# Generated deterministically by seda-macro-lef-normalizer-v1; recipe orfs-ng45-fakeram-metal3-coupledl2-pg-v1.
VERSION 5.8 ;
BUSBITCHARS "[]" ;
DIVIDERCHAR "/" ;

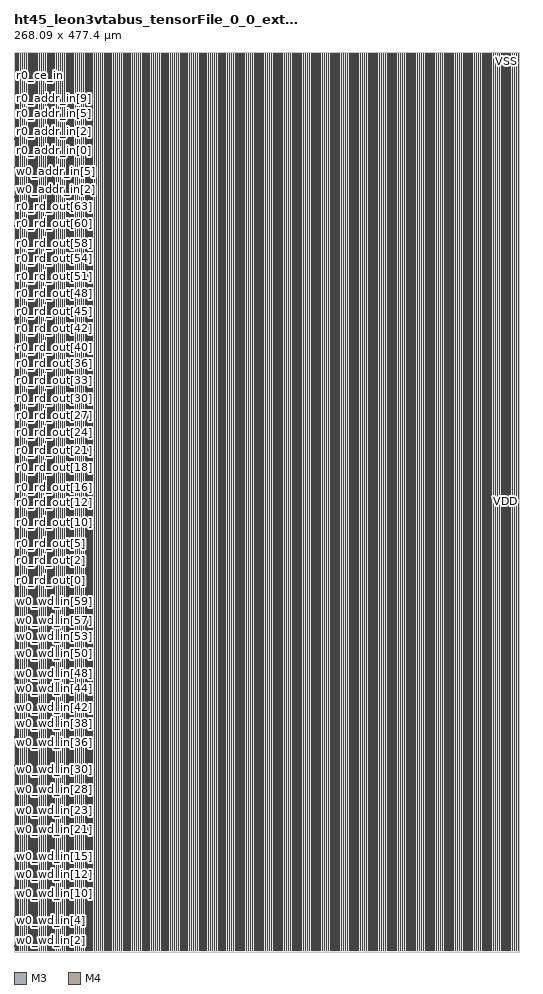
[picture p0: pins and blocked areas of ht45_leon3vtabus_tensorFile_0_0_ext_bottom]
MACRO ht45_leon3vtabus_tensorFile_0_0_ext_bottom
  FOREIGN ht45_leon3vtabus_tensorFile_0_0_ext_bottom 0 0 ;
  CLASS BLOCK ;
  ORIGIN 0 0 ;
  SIZE 268.09 BY 477.4 ;
  SYMMETRY X Y R90 ;
  PIN w0_wd_in[0]
    DIRECTION INPUT ;
    USE SIGNAL ;
    SHAPE ABUTMENT ;
    PORT
      LAYER M3 ;
      RECT 0 0.035 0.07 0.105 ;
    END
  END w0_wd_in[0]
  PIN w0_wd_in[1]
    DIRECTION INPUT ;
    USE SIGNAL ;
    SHAPE ABUTMENT ;
    PORT
      LAYER M3 ;
      RECT 0 3.115 0.07 3.185 ;
    END
  END w0_wd_in[1]
  PIN w0_wd_in[2]
    DIRECTION INPUT ;
    USE SIGNAL ;
    SHAPE ABUTMENT ;
    PORT
      LAYER M3 ;
      RECT 0 6.195 0.07 6.265 ;
    END
  END w0_wd_in[2]
  PIN w0_wd_in[3]
    DIRECTION INPUT ;
    USE SIGNAL ;
    SHAPE ABUTMENT ;
    PORT
      LAYER M3 ;
      RECT 0 9.275 0.07 9.345 ;
    END
  END w0_wd_in[3]
  PIN w0_wd_in[4]
    DIRECTION INPUT ;
    USE SIGNAL ;
    SHAPE ABUTMENT ;
    PORT
      LAYER M3 ;
      RECT 0 12.355 0.07 12.425 ;
    END
  END w0_wd_in[4]
  PIN w0_wd_in[5]
    DIRECTION INPUT ;
    USE SIGNAL ;
    SHAPE ABUTMENT ;
    PORT
      LAYER M3 ;
      RECT 0 15.435 0.07 15.505 ;
    END
  END w0_wd_in[5]
  PIN w0_wd_in[6]
    DIRECTION INPUT ;
    USE SIGNAL ;
    SHAPE ABUTMENT ;
    PORT
      LAYER M3 ;
      RECT 0 18.515 0.07 18.585 ;
    END
  END w0_wd_in[6]
  PIN w0_wd_in[7]
    DIRECTION INPUT ;
    USE SIGNAL ;
    SHAPE ABUTMENT ;
    PORT
      LAYER M3 ;
      RECT 0 21.595 0.07 21.665 ;
    END
  END w0_wd_in[7]
  PIN w0_wd_in[8]
    DIRECTION INPUT ;
    USE SIGNAL ;
    SHAPE ABUTMENT ;
    PORT
      LAYER M3 ;
      RECT 0 24.675 0.07 24.745 ;
    END
  END w0_wd_in[8]
  PIN w0_wd_in[9]
    DIRECTION INPUT ;
    USE SIGNAL ;
    SHAPE ABUTMENT ;
    PORT
      LAYER M3 ;
      RECT 0 27.755 0.07 27.825 ;
    END
  END w0_wd_in[9]
  PIN w0_wd_in[10]
    DIRECTION INPUT ;
    USE SIGNAL ;
    SHAPE ABUTMENT ;
    PORT
      LAYER M3 ;
      RECT 0 30.835 0.07 30.905 ;
    END
  END w0_wd_in[10]
  PIN w0_wd_in[11]
    DIRECTION INPUT ;
    USE SIGNAL ;
    SHAPE ABUTMENT ;
    PORT
      LAYER M3 ;
      RECT 0 33.915 0.07 33.985 ;
    END
  END w0_wd_in[11]
  PIN w0_wd_in[12]
    DIRECTION INPUT ;
    USE SIGNAL ;
    SHAPE ABUTMENT ;
    PORT
      LAYER M3 ;
      RECT 0 36.995 0.07 37.065 ;
    END
  END w0_wd_in[12]
  PIN w0_wd_in[13]
    DIRECTION INPUT ;
    USE SIGNAL ;
    SHAPE ABUTMENT ;
    PORT
      LAYER M3 ;
      RECT 0 40.075 0.07 40.145 ;
    END
  END w0_wd_in[13]
  PIN w0_wd_in[14]
    DIRECTION INPUT ;
    USE SIGNAL ;
    SHAPE ABUTMENT ;
    PORT
      LAYER M3 ;
      RECT 0 43.155 0.07 43.225 ;
    END
  END w0_wd_in[14]
  PIN w0_wd_in[15]
    DIRECTION INPUT ;
    USE SIGNAL ;
    SHAPE ABUTMENT ;
    PORT
      LAYER M3 ;
      RECT 0 46.235 0.07 46.305 ;
    END
  END w0_wd_in[15]
  PIN w0_wd_in[16]
    DIRECTION INPUT ;
    USE SIGNAL ;
    SHAPE ABUTMENT ;
    PORT
      LAYER M3 ;
      RECT 0 49.315 0.07 49.385 ;
    END
  END w0_wd_in[16]
  PIN w0_wd_in[17]
    DIRECTION INPUT ;
    USE SIGNAL ;
    SHAPE ABUTMENT ;
    PORT
      LAYER M3 ;
      RECT 0 52.395 0.07 52.465 ;
    END
  END w0_wd_in[17]
  PIN w0_wd_in[18]
    DIRECTION INPUT ;
    USE SIGNAL ;
    SHAPE ABUTMENT ;
    PORT
      LAYER M3 ;
      RECT 0 55.475 0.07 55.545 ;
    END
  END w0_wd_in[18]
  PIN w0_wd_in[19]
    DIRECTION INPUT ;
    USE SIGNAL ;
    SHAPE ABUTMENT ;
    PORT
      LAYER M3 ;
      RECT 0 58.555 0.07 58.625 ;
    END
  END w0_wd_in[19]
  PIN w0_wd_in[20]
    DIRECTION INPUT ;
    USE SIGNAL ;
    SHAPE ABUTMENT ;
    PORT
      LAYER M3 ;
      RECT 0 61.635 0.07 61.705 ;
    END
  END w0_wd_in[20]
  PIN w0_wd_in[21]
    DIRECTION INPUT ;
    USE SIGNAL ;
    SHAPE ABUTMENT ;
    PORT
      LAYER M3 ;
      RECT 0 64.715 0.07 64.785 ;
    END
  END w0_wd_in[21]
  PIN w0_wd_in[22]
    DIRECTION INPUT ;
    USE SIGNAL ;
    SHAPE ABUTMENT ;
    PORT
      LAYER M3 ;
      RECT 0 67.795 0.07 67.865 ;
    END
  END w0_wd_in[22]
  PIN w0_wd_in[23]
    DIRECTION INPUT ;
    USE SIGNAL ;
    SHAPE ABUTMENT ;
    PORT
      LAYER M3 ;
      RECT 0 70.875 0.07 70.945 ;
    END
  END w0_wd_in[23]
  PIN w0_wd_in[24]
    DIRECTION INPUT ;
    USE SIGNAL ;
    SHAPE ABUTMENT ;
    PORT
      LAYER M3 ;
      RECT 0 73.955 0.07 74.025 ;
    END
  END w0_wd_in[24]
  PIN w0_wd_in[25]
    DIRECTION INPUT ;
    USE SIGNAL ;
    SHAPE ABUTMENT ;
    PORT
      LAYER M3 ;
      RECT 0 77.035 0.07 77.105 ;
    END
  END w0_wd_in[25]
  PIN w0_wd_in[26]
    DIRECTION INPUT ;
    USE SIGNAL ;
    SHAPE ABUTMENT ;
    PORT
      LAYER M3 ;
      RECT 0 80.115 0.07 80.185 ;
    END
  END w0_wd_in[26]
  PIN w0_wd_in[27]
    DIRECTION INPUT ;
    USE SIGNAL ;
    SHAPE ABUTMENT ;
    PORT
      LAYER M3 ;
      RECT 0 83.195 0.07 83.265 ;
    END
  END w0_wd_in[27]
  PIN w0_wd_in[28]
    DIRECTION INPUT ;
    USE SIGNAL ;
    SHAPE ABUTMENT ;
    PORT
      LAYER M3 ;
      RECT 0 86.275 0.07 86.345 ;
    END
  END w0_wd_in[28]
  PIN w0_wd_in[29]
    DIRECTION INPUT ;
    USE SIGNAL ;
    SHAPE ABUTMENT ;
    PORT
      LAYER M3 ;
      RECT 0 89.355 0.07 89.425 ;
    END
  END w0_wd_in[29]
  PIN w0_wd_in[30]
    DIRECTION INPUT ;
    USE SIGNAL ;
    SHAPE ABUTMENT ;
    PORT
      LAYER M3 ;
      RECT 0 92.435 0.07 92.505 ;
    END
  END w0_wd_in[30]
  PIN w0_wd_in[31]
    DIRECTION INPUT ;
    USE SIGNAL ;
    SHAPE ABUTMENT ;
    PORT
      LAYER M3 ;
      RECT 0 95.515 0.07 95.585 ;
    END
  END w0_wd_in[31]
  PIN w0_wd_in[32]
    DIRECTION INPUT ;
    USE SIGNAL ;
    SHAPE ABUTMENT ;
    PORT
      LAYER M3 ;
      RECT 0 98.595 0.07 98.665 ;
    END
  END w0_wd_in[32]
  PIN w0_wd_in[33]
    DIRECTION INPUT ;
    USE SIGNAL ;
    SHAPE ABUTMENT ;
    PORT
      LAYER M3 ;
      RECT 0 101.675 0.07 101.745 ;
    END
  END w0_wd_in[33]
  PIN w0_wd_in[34]
    DIRECTION INPUT ;
    USE SIGNAL ;
    SHAPE ABUTMENT ;
    PORT
      LAYER M3 ;
      RECT 0 104.755 0.07 104.825 ;
    END
  END w0_wd_in[34]
  PIN w0_wd_in[35]
    DIRECTION INPUT ;
    USE SIGNAL ;
    SHAPE ABUTMENT ;
    PORT
      LAYER M3 ;
      RECT 0 107.835 0.07 107.905 ;
    END
  END w0_wd_in[35]
  PIN w0_wd_in[36]
    DIRECTION INPUT ;
    USE SIGNAL ;
    SHAPE ABUTMENT ;
    PORT
      LAYER M3 ;
      RECT 0 110.915 0.07 110.985 ;
    END
  END w0_wd_in[36]
  PIN w0_wd_in[37]
    DIRECTION INPUT ;
    USE SIGNAL ;
    SHAPE ABUTMENT ;
    PORT
      LAYER M3 ;
      RECT 0 113.995 0.07 114.065 ;
    END
  END w0_wd_in[37]
  PIN w0_wd_in[38]
    DIRECTION INPUT ;
    USE SIGNAL ;
    SHAPE ABUTMENT ;
    PORT
      LAYER M3 ;
      RECT 0 117.075 0.07 117.145 ;
    END
  END w0_wd_in[38]
  PIN w0_wd_in[39]
    DIRECTION INPUT ;
    USE SIGNAL ;
    SHAPE ABUTMENT ;
    PORT
      LAYER M3 ;
      RECT 0 120.155 0.07 120.225 ;
    END
  END w0_wd_in[39]
  PIN w0_wd_in[40]
    DIRECTION INPUT ;
    USE SIGNAL ;
    SHAPE ABUTMENT ;
    PORT
      LAYER M3 ;
      RECT 0 123.235 0.07 123.305 ;
    END
  END w0_wd_in[40]
  PIN w0_wd_in[41]
    DIRECTION INPUT ;
    USE SIGNAL ;
    SHAPE ABUTMENT ;
    PORT
      LAYER M3 ;
      RECT 0 126.315 0.07 126.385 ;
    END
  END w0_wd_in[41]
  PIN w0_wd_in[42]
    DIRECTION INPUT ;
    USE SIGNAL ;
    SHAPE ABUTMENT ;
    PORT
      LAYER M3 ;
      RECT 0 129.395 0.07 129.465 ;
    END
  END w0_wd_in[42]
  PIN w0_wd_in[43]
    DIRECTION INPUT ;
    USE SIGNAL ;
    SHAPE ABUTMENT ;
    PORT
      LAYER M3 ;
      RECT 0 132.475 0.07 132.545 ;
    END
  END w0_wd_in[43]
  PIN w0_wd_in[44]
    DIRECTION INPUT ;
    USE SIGNAL ;
    SHAPE ABUTMENT ;
    PORT
      LAYER M3 ;
      RECT 0 135.555 0.07 135.625 ;
    END
  END w0_wd_in[44]
  PIN w0_wd_in[45]
    DIRECTION INPUT ;
    USE SIGNAL ;
    SHAPE ABUTMENT ;
    PORT
      LAYER M3 ;
      RECT 0 138.635 0.07 138.705 ;
    END
  END w0_wd_in[45]
  PIN w0_wd_in[46]
    DIRECTION INPUT ;
    USE SIGNAL ;
    SHAPE ABUTMENT ;
    PORT
      LAYER M3 ;
      RECT 0 141.715 0.07 141.785 ;
    END
  END w0_wd_in[46]
  PIN w0_wd_in[47]
    DIRECTION INPUT ;
    USE SIGNAL ;
    SHAPE ABUTMENT ;
    PORT
      LAYER M3 ;
      RECT 0 144.795 0.07 144.865 ;
    END
  END w0_wd_in[47]
  PIN w0_wd_in[48]
    DIRECTION INPUT ;
    USE SIGNAL ;
    SHAPE ABUTMENT ;
    PORT
      LAYER M3 ;
      RECT 0 147.875 0.07 147.945 ;
    END
  END w0_wd_in[48]
  PIN w0_wd_in[49]
    DIRECTION INPUT ;
    USE SIGNAL ;
    SHAPE ABUTMENT ;
    PORT
      LAYER M3 ;
      RECT 0 150.955 0.07 151.025 ;
    END
  END w0_wd_in[49]
  PIN w0_wd_in[50]
    DIRECTION INPUT ;
    USE SIGNAL ;
    SHAPE ABUTMENT ;
    PORT
      LAYER M3 ;
      RECT 0 154.035 0.07 154.105 ;
    END
  END w0_wd_in[50]
  PIN w0_wd_in[51]
    DIRECTION INPUT ;
    USE SIGNAL ;
    SHAPE ABUTMENT ;
    PORT
      LAYER M3 ;
      RECT 0 157.115 0.07 157.185 ;
    END
  END w0_wd_in[51]
  PIN w0_wd_in[52]
    DIRECTION INPUT ;
    USE SIGNAL ;
    SHAPE ABUTMENT ;
    PORT
      LAYER M3 ;
      RECT 0 160.195 0.07 160.265 ;
    END
  END w0_wd_in[52]
  PIN w0_wd_in[53]
    DIRECTION INPUT ;
    USE SIGNAL ;
    SHAPE ABUTMENT ;
    PORT
      LAYER M3 ;
      RECT 0 163.275 0.07 163.345 ;
    END
  END w0_wd_in[53]
  PIN w0_wd_in[54]
    DIRECTION INPUT ;
    USE SIGNAL ;
    SHAPE ABUTMENT ;
    PORT
      LAYER M3 ;
      RECT 0 166.355 0.07 166.425 ;
    END
  END w0_wd_in[54]
  PIN w0_wd_in[55]
    DIRECTION INPUT ;
    USE SIGNAL ;
    SHAPE ABUTMENT ;
    PORT
      LAYER M3 ;
      RECT 0 169.435 0.07 169.505 ;
    END
  END w0_wd_in[55]
  PIN w0_wd_in[56]
    DIRECTION INPUT ;
    USE SIGNAL ;
    SHAPE ABUTMENT ;
    PORT
      LAYER M3 ;
      RECT 0 172.515 0.07 172.585 ;
    END
  END w0_wd_in[56]
  PIN w0_wd_in[57]
    DIRECTION INPUT ;
    USE SIGNAL ;
    SHAPE ABUTMENT ;
    PORT
      LAYER M3 ;
      RECT 0 175.595 0.07 175.665 ;
    END
  END w0_wd_in[57]
  PIN w0_wd_in[58]
    DIRECTION INPUT ;
    USE SIGNAL ;
    SHAPE ABUTMENT ;
    PORT
      LAYER M3 ;
      RECT 0 178.675 0.07 178.745 ;
    END
  END w0_wd_in[58]
  PIN w0_wd_in[59]
    DIRECTION INPUT ;
    USE SIGNAL ;
    SHAPE ABUTMENT ;
    PORT
      LAYER M3 ;
      RECT 0 181.755 0.07 181.825 ;
    END
  END w0_wd_in[59]
  PIN w0_wd_in[60]
    DIRECTION INPUT ;
    USE SIGNAL ;
    SHAPE ABUTMENT ;
    PORT
      LAYER M3 ;
      RECT 0 184.835 0.07 184.905 ;
    END
  END w0_wd_in[60]
  PIN w0_wd_in[61]
    DIRECTION INPUT ;
    USE SIGNAL ;
    SHAPE ABUTMENT ;
    PORT
      LAYER M3 ;
      RECT 0 187.915 0.07 187.985 ;
    END
  END w0_wd_in[61]
  PIN w0_wd_in[62]
    DIRECTION INPUT ;
    USE SIGNAL ;
    SHAPE ABUTMENT ;
    PORT
      LAYER M3 ;
      RECT 0 190.995 0.07 191.065 ;
    END
  END w0_wd_in[62]
  PIN w0_wd_in[63]
    DIRECTION INPUT ;
    USE SIGNAL ;
    SHAPE ABUTMENT ;
    PORT
      LAYER M3 ;
      RECT 0 194.075 0.07 194.145 ;
    END
  END w0_wd_in[63]
  PIN r0_rd_out[0]
    DIRECTION OUTPUT ;
    USE SIGNAL ;
    SHAPE ABUTMENT ;
    PORT
      LAYER M3 ;
      RECT 0 197.155 0.07 197.225 ;
    END
  END r0_rd_out[0]
  PIN r0_rd_out[1]
    DIRECTION OUTPUT ;
    USE SIGNAL ;
    SHAPE ABUTMENT ;
    PORT
      LAYER M3 ;
      RECT 0 200.235 0.07 200.305 ;
    END
  END r0_rd_out[1]
  PIN r0_rd_out[2]
    DIRECTION OUTPUT ;
    USE SIGNAL ;
    SHAPE ABUTMENT ;
    PORT
      LAYER M3 ;
      RECT 0 203.315 0.07 203.385 ;
    END
  END r0_rd_out[2]
  PIN r0_rd_out[3]
    DIRECTION OUTPUT ;
    USE SIGNAL ;
    SHAPE ABUTMENT ;
    PORT
      LAYER M3 ;
      RECT 0 206.395 0.07 206.465 ;
    END
  END r0_rd_out[3]
  PIN r0_rd_out[4]
    DIRECTION OUTPUT ;
    USE SIGNAL ;
    SHAPE ABUTMENT ;
    PORT
      LAYER M3 ;
      RECT 0 209.475 0.07 209.545 ;
    END
  END r0_rd_out[4]
  PIN r0_rd_out[5]
    DIRECTION OUTPUT ;
    USE SIGNAL ;
    SHAPE ABUTMENT ;
    PORT
      LAYER M3 ;
      RECT 0 212.555 0.07 212.625 ;
    END
  END r0_rd_out[5]
  PIN r0_rd_out[6]
    DIRECTION OUTPUT ;
    USE SIGNAL ;
    SHAPE ABUTMENT ;
    PORT
      LAYER M3 ;
      RECT 0 215.635 0.07 215.705 ;
    END
  END r0_rd_out[6]
  PIN r0_rd_out[7]
    DIRECTION OUTPUT ;
    USE SIGNAL ;
    SHAPE ABUTMENT ;
    PORT
      LAYER M3 ;
      RECT 0 218.715 0.07 218.785 ;
    END
  END r0_rd_out[7]
  PIN r0_rd_out[8]
    DIRECTION OUTPUT ;
    USE SIGNAL ;
    SHAPE ABUTMENT ;
    PORT
      LAYER M3 ;
      RECT 0 221.795 0.07 221.865 ;
    END
  END r0_rd_out[8]
  PIN r0_rd_out[9]
    DIRECTION OUTPUT ;
    USE SIGNAL ;
    SHAPE ABUTMENT ;
    PORT
      LAYER M3 ;
      RECT 0 224.875 0.07 224.945 ;
    END
  END r0_rd_out[9]
  PIN r0_rd_out[10]
    DIRECTION OUTPUT ;
    USE SIGNAL ;
    SHAPE ABUTMENT ;
    PORT
      LAYER M3 ;
      RECT 0 227.955 0.07 228.025 ;
    END
  END r0_rd_out[10]
  PIN r0_rd_out[11]
    DIRECTION OUTPUT ;
    USE SIGNAL ;
    SHAPE ABUTMENT ;
    PORT
      LAYER M3 ;
      RECT 0 231.035 0.07 231.105 ;
    END
  END r0_rd_out[11]
  PIN r0_rd_out[12]
    DIRECTION OUTPUT ;
    USE SIGNAL ;
    SHAPE ABUTMENT ;
    PORT
      LAYER M3 ;
      RECT 0 234.115 0.07 234.185 ;
    END
  END r0_rd_out[12]
  PIN r0_rd_out[13]
    DIRECTION OUTPUT ;
    USE SIGNAL ;
    SHAPE ABUTMENT ;
    PORT
      LAYER M3 ;
      RECT 0 237.195 0.07 237.265 ;
    END
  END r0_rd_out[13]
  PIN r0_rd_out[14]
    DIRECTION OUTPUT ;
    USE SIGNAL ;
    SHAPE ABUTMENT ;
    PORT
      LAYER M3 ;
      RECT 0 240.275 0.07 240.345 ;
    END
  END r0_rd_out[14]
  PIN r0_rd_out[15]
    DIRECTION OUTPUT ;
    USE SIGNAL ;
    SHAPE ABUTMENT ;
    PORT
      LAYER M3 ;
      RECT 0 243.355 0.07 243.425 ;
    END
  END r0_rd_out[15]
  PIN r0_rd_out[16]
    DIRECTION OUTPUT ;
    USE SIGNAL ;
    SHAPE ABUTMENT ;
    PORT
      LAYER M3 ;
      RECT 0 246.435 0.07 246.505 ;
    END
  END r0_rd_out[16]
  PIN r0_rd_out[17]
    DIRECTION OUTPUT ;
    USE SIGNAL ;
    SHAPE ABUTMENT ;
    PORT
      LAYER M3 ;
      RECT 0 249.515 0.07 249.585 ;
    END
  END r0_rd_out[17]
  PIN r0_rd_out[18]
    DIRECTION OUTPUT ;
    USE SIGNAL ;
    SHAPE ABUTMENT ;
    PORT
      LAYER M3 ;
      RECT 0 252.595 0.07 252.665 ;
    END
  END r0_rd_out[18]
  PIN r0_rd_out[19]
    DIRECTION OUTPUT ;
    USE SIGNAL ;
    SHAPE ABUTMENT ;
    PORT
      LAYER M3 ;
      RECT 0 255.675 0.07 255.745 ;
    END
  END r0_rd_out[19]
  PIN r0_rd_out[20]
    DIRECTION OUTPUT ;
    USE SIGNAL ;
    SHAPE ABUTMENT ;
    PORT
      LAYER M3 ;
      RECT 0 258.755 0.07 258.825 ;
    END
  END r0_rd_out[20]
  PIN r0_rd_out[21]
    DIRECTION OUTPUT ;
    USE SIGNAL ;
    SHAPE ABUTMENT ;
    PORT
      LAYER M3 ;
      RECT 0 261.835 0.07 261.905 ;
    END
  END r0_rd_out[21]
  PIN r0_rd_out[22]
    DIRECTION OUTPUT ;
    USE SIGNAL ;
    SHAPE ABUTMENT ;
    PORT
      LAYER M3 ;
      RECT 0 264.915 0.07 264.985 ;
    END
  END r0_rd_out[22]
  PIN r0_rd_out[23]
    DIRECTION OUTPUT ;
    USE SIGNAL ;
    SHAPE ABUTMENT ;
    PORT
      LAYER M3 ;
      RECT 0 267.995 0.07 268.065 ;
    END
  END r0_rd_out[23]
  PIN r0_rd_out[24]
    DIRECTION OUTPUT ;
    USE SIGNAL ;
    SHAPE ABUTMENT ;
    PORT
      LAYER M3 ;
      RECT 0 271.075 0.07 271.145 ;
    END
  END r0_rd_out[24]
  PIN r0_rd_out[25]
    DIRECTION OUTPUT ;
    USE SIGNAL ;
    SHAPE ABUTMENT ;
    PORT
      LAYER M3 ;
      RECT 0 274.155 0.07 274.225 ;
    END
  END r0_rd_out[25]
  PIN r0_rd_out[26]
    DIRECTION OUTPUT ;
    USE SIGNAL ;
    SHAPE ABUTMENT ;
    PORT
      LAYER M3 ;
      RECT 0 277.235 0.07 277.305 ;
    END
  END r0_rd_out[26]
  PIN r0_rd_out[27]
    DIRECTION OUTPUT ;
    USE SIGNAL ;
    SHAPE ABUTMENT ;
    PORT
      LAYER M3 ;
      RECT 0 280.315 0.07 280.385 ;
    END
  END r0_rd_out[27]
  PIN r0_rd_out[28]
    DIRECTION OUTPUT ;
    USE SIGNAL ;
    SHAPE ABUTMENT ;
    PORT
      LAYER M3 ;
      RECT 0 283.395 0.07 283.465 ;
    END
  END r0_rd_out[28]
  PIN r0_rd_out[29]
    DIRECTION OUTPUT ;
    USE SIGNAL ;
    SHAPE ABUTMENT ;
    PORT
      LAYER M3 ;
      RECT 0 286.475 0.07 286.545 ;
    END
  END r0_rd_out[29]
  PIN r0_rd_out[30]
    DIRECTION OUTPUT ;
    USE SIGNAL ;
    SHAPE ABUTMENT ;
    PORT
      LAYER M3 ;
      RECT 0 289.555 0.07 289.625 ;
    END
  END r0_rd_out[30]
  PIN r0_rd_out[31]
    DIRECTION OUTPUT ;
    USE SIGNAL ;
    SHAPE ABUTMENT ;
    PORT
      LAYER M3 ;
      RECT 0 292.635 0.07 292.705 ;
    END
  END r0_rd_out[31]
  PIN r0_rd_out[32]
    DIRECTION OUTPUT ;
    USE SIGNAL ;
    SHAPE ABUTMENT ;
    PORT
      LAYER M3 ;
      RECT 0 295.715 0.07 295.785 ;
    END
  END r0_rd_out[32]
  PIN r0_rd_out[33]
    DIRECTION OUTPUT ;
    USE SIGNAL ;
    SHAPE ABUTMENT ;
    PORT
      LAYER M3 ;
      RECT 0 298.795 0.07 298.865 ;
    END
  END r0_rd_out[33]
  PIN r0_rd_out[34]
    DIRECTION OUTPUT ;
    USE SIGNAL ;
    SHAPE ABUTMENT ;
    PORT
      LAYER M3 ;
      RECT 0 301.875 0.07 301.945 ;
    END
  END r0_rd_out[34]
  PIN r0_rd_out[35]
    DIRECTION OUTPUT ;
    USE SIGNAL ;
    SHAPE ABUTMENT ;
    PORT
      LAYER M3 ;
      RECT 0 304.955 0.07 305.025 ;
    END
  END r0_rd_out[35]
  PIN r0_rd_out[36]
    DIRECTION OUTPUT ;
    USE SIGNAL ;
    SHAPE ABUTMENT ;
    PORT
      LAYER M3 ;
      RECT 0 308.035 0.07 308.105 ;
    END
  END r0_rd_out[36]
  PIN r0_rd_out[37]
    DIRECTION OUTPUT ;
    USE SIGNAL ;
    SHAPE ABUTMENT ;
    PORT
      LAYER M3 ;
      RECT 0 311.115 0.07 311.185 ;
    END
  END r0_rd_out[37]
  PIN r0_rd_out[38]
    DIRECTION OUTPUT ;
    USE SIGNAL ;
    SHAPE ABUTMENT ;
    PORT
      LAYER M3 ;
      RECT 0 314.195 0.07 314.265 ;
    END
  END r0_rd_out[38]
  PIN r0_rd_out[39]
    DIRECTION OUTPUT ;
    USE SIGNAL ;
    SHAPE ABUTMENT ;
    PORT
      LAYER M3 ;
      RECT 0 317.275 0.07 317.345 ;
    END
  END r0_rd_out[39]
  PIN r0_rd_out[40]
    DIRECTION OUTPUT ;
    USE SIGNAL ;
    SHAPE ABUTMENT ;
    PORT
      LAYER M3 ;
      RECT 0 320.355 0.07 320.425 ;
    END
  END r0_rd_out[40]
  PIN r0_rd_out[41]
    DIRECTION OUTPUT ;
    USE SIGNAL ;
    SHAPE ABUTMENT ;
    PORT
      LAYER M3 ;
      RECT 0 323.435 0.07 323.505 ;
    END
  END r0_rd_out[41]
  PIN r0_rd_out[42]
    DIRECTION OUTPUT ;
    USE SIGNAL ;
    SHAPE ABUTMENT ;
    PORT
      LAYER M3 ;
      RECT 0 326.515 0.07 326.585 ;
    END
  END r0_rd_out[42]
  PIN r0_rd_out[43]
    DIRECTION OUTPUT ;
    USE SIGNAL ;
    SHAPE ABUTMENT ;
    PORT
      LAYER M3 ;
      RECT 0 329.595 0.07 329.665 ;
    END
  END r0_rd_out[43]
  PIN r0_rd_out[44]
    DIRECTION OUTPUT ;
    USE SIGNAL ;
    SHAPE ABUTMENT ;
    PORT
      LAYER M3 ;
      RECT 0 332.675 0.07 332.745 ;
    END
  END r0_rd_out[44]
  PIN r0_rd_out[45]
    DIRECTION OUTPUT ;
    USE SIGNAL ;
    SHAPE ABUTMENT ;
    PORT
      LAYER M3 ;
      RECT 0 335.755 0.07 335.825 ;
    END
  END r0_rd_out[45]
  PIN r0_rd_out[46]
    DIRECTION OUTPUT ;
    USE SIGNAL ;
    SHAPE ABUTMENT ;
    PORT
      LAYER M3 ;
      RECT 0 338.835 0.07 338.905 ;
    END
  END r0_rd_out[46]
  PIN r0_rd_out[47]
    DIRECTION OUTPUT ;
    USE SIGNAL ;
    SHAPE ABUTMENT ;
    PORT
      LAYER M3 ;
      RECT 0 341.915 0.07 341.985 ;
    END
  END r0_rd_out[47]
  PIN r0_rd_out[48]
    DIRECTION OUTPUT ;
    USE SIGNAL ;
    SHAPE ABUTMENT ;
    PORT
      LAYER M3 ;
      RECT 0 344.995 0.07 345.065 ;
    END
  END r0_rd_out[48]
  PIN r0_rd_out[49]
    DIRECTION OUTPUT ;
    USE SIGNAL ;
    SHAPE ABUTMENT ;
    PORT
      LAYER M3 ;
      RECT 0 348.075 0.07 348.145 ;
    END
  END r0_rd_out[49]
  PIN r0_rd_out[50]
    DIRECTION OUTPUT ;
    USE SIGNAL ;
    SHAPE ABUTMENT ;
    PORT
      LAYER M3 ;
      RECT 0 351.155 0.07 351.225 ;
    END
  END r0_rd_out[50]
  PIN r0_rd_out[51]
    DIRECTION OUTPUT ;
    USE SIGNAL ;
    SHAPE ABUTMENT ;
    PORT
      LAYER M3 ;
      RECT 0 354.235 0.07 354.305 ;
    END
  END r0_rd_out[51]
  PIN r0_rd_out[52]
    DIRECTION OUTPUT ;
    USE SIGNAL ;
    SHAPE ABUTMENT ;
    PORT
      LAYER M3 ;
      RECT 0 357.315 0.07 357.385 ;
    END
  END r0_rd_out[52]
  PIN r0_rd_out[53]
    DIRECTION OUTPUT ;
    USE SIGNAL ;
    SHAPE ABUTMENT ;
    PORT
      LAYER M3 ;
      RECT 0 360.395 0.07 360.465 ;
    END
  END r0_rd_out[53]
  PIN r0_rd_out[54]
    DIRECTION OUTPUT ;
    USE SIGNAL ;
    SHAPE ABUTMENT ;
    PORT
      LAYER M3 ;
      RECT 0 363.475 0.07 363.545 ;
    END
  END r0_rd_out[54]
  PIN r0_rd_out[55]
    DIRECTION OUTPUT ;
    USE SIGNAL ;
    SHAPE ABUTMENT ;
    PORT
      LAYER M3 ;
      RECT 0 366.555 0.07 366.625 ;
    END
  END r0_rd_out[55]
  PIN r0_rd_out[56]
    DIRECTION OUTPUT ;
    USE SIGNAL ;
    SHAPE ABUTMENT ;
    PORT
      LAYER M3 ;
      RECT 0 369.635 0.07 369.705 ;
    END
  END r0_rd_out[56]
  PIN r0_rd_out[57]
    DIRECTION OUTPUT ;
    USE SIGNAL ;
    SHAPE ABUTMENT ;
    PORT
      LAYER M3 ;
      RECT 0 372.715 0.07 372.785 ;
    END
  END r0_rd_out[57]
  PIN r0_rd_out[58]
    DIRECTION OUTPUT ;
    USE SIGNAL ;
    SHAPE ABUTMENT ;
    PORT
      LAYER M3 ;
      RECT 0 375.795 0.07 375.865 ;
    END
  END r0_rd_out[58]
  PIN r0_rd_out[59]
    DIRECTION OUTPUT ;
    USE SIGNAL ;
    SHAPE ABUTMENT ;
    PORT
      LAYER M3 ;
      RECT 0 378.875 0.07 378.945 ;
    END
  END r0_rd_out[59]
  PIN r0_rd_out[60]
    DIRECTION OUTPUT ;
    USE SIGNAL ;
    SHAPE ABUTMENT ;
    PORT
      LAYER M3 ;
      RECT 0 381.955 0.07 382.025 ;
    END
  END r0_rd_out[60]
  PIN r0_rd_out[61]
    DIRECTION OUTPUT ;
    USE SIGNAL ;
    SHAPE ABUTMENT ;
    PORT
      LAYER M3 ;
      RECT 0 385.035 0.07 385.105 ;
    END
  END r0_rd_out[61]
  PIN r0_rd_out[62]
    DIRECTION OUTPUT ;
    USE SIGNAL ;
    SHAPE ABUTMENT ;
    PORT
      LAYER M3 ;
      RECT 0 388.115 0.07 388.185 ;
    END
  END r0_rd_out[62]
  PIN r0_rd_out[63]
    DIRECTION OUTPUT ;
    USE SIGNAL ;
    SHAPE ABUTMENT ;
    PORT
      LAYER M3 ;
      RECT 0 391.195 0.07 391.265 ;
    END
  END r0_rd_out[63]
  PIN w0_addr_in[0]
    DIRECTION INPUT ;
    USE SIGNAL ;
    SHAPE ABUTMENT ;
    PORT
      LAYER M3 ;
      RECT 0 394.275 0.07 394.345 ;
    END
  END w0_addr_in[0]
  PIN w0_addr_in[1]
    DIRECTION INPUT ;
    USE SIGNAL ;
    SHAPE ABUTMENT ;
    PORT
      LAYER M3 ;
      RECT 0 397.355 0.07 397.425 ;
    END
  END w0_addr_in[1]
  PIN w0_addr_in[2]
    DIRECTION INPUT ;
    USE SIGNAL ;
    SHAPE ABUTMENT ;
    PORT
      LAYER M3 ;
      RECT 0 400.435 0.07 400.505 ;
    END
  END w0_addr_in[2]
  PIN w0_addr_in[3]
    DIRECTION INPUT ;
    USE SIGNAL ;
    SHAPE ABUTMENT ;
    PORT
      LAYER M3 ;
      RECT 0 403.515 0.07 403.585 ;
    END
  END w0_addr_in[3]
  PIN w0_addr_in[4]
    DIRECTION INPUT ;
    USE SIGNAL ;
    SHAPE ABUTMENT ;
    PORT
      LAYER M3 ;
      RECT 0 406.595 0.07 406.665 ;
    END
  END w0_addr_in[4]
  PIN w0_addr_in[5]
    DIRECTION INPUT ;
    USE SIGNAL ;
    SHAPE ABUTMENT ;
    PORT
      LAYER M3 ;
      RECT 0 409.675 0.07 409.745 ;
    END
  END w0_addr_in[5]
  PIN w0_addr_in[6]
    DIRECTION INPUT ;
    USE SIGNAL ;
    SHAPE ABUTMENT ;
    PORT
      LAYER M3 ;
      RECT 0 412.755 0.07 412.825 ;
    END
  END w0_addr_in[6]
  PIN w0_addr_in[7]
    DIRECTION INPUT ;
    USE SIGNAL ;
    SHAPE ABUTMENT ;
    PORT
      LAYER M3 ;
      RECT 0 415.835 0.07 415.905 ;
    END
  END w0_addr_in[7]
  PIN w0_addr_in[8]
    DIRECTION INPUT ;
    USE SIGNAL ;
    SHAPE ABUTMENT ;
    PORT
      LAYER M3 ;
      RECT 0 418.915 0.07 418.985 ;
    END
  END w0_addr_in[8]
  PIN w0_addr_in[9]
    DIRECTION INPUT ;
    USE SIGNAL ;
    SHAPE ABUTMENT ;
    PORT
      LAYER M3 ;
      RECT 0 421.995 0.07 422.065 ;
    END
  END w0_addr_in[9]
  PIN r0_addr_in[0]
    DIRECTION INPUT ;
    USE SIGNAL ;
    SHAPE ABUTMENT ;
    PORT
      LAYER M3 ;
      RECT 0 425.075 0.07 425.145 ;
    END
  END r0_addr_in[0]
  PIN r0_addr_in[1]
    DIRECTION INPUT ;
    USE SIGNAL ;
    SHAPE ABUTMENT ;
    PORT
      LAYER M3 ;
      RECT 0 428.155 0.07 428.225 ;
    END
  END r0_addr_in[1]
  PIN r0_addr_in[2]
    DIRECTION INPUT ;
    USE SIGNAL ;
    SHAPE ABUTMENT ;
    PORT
      LAYER M3 ;
      RECT 0 431.235 0.07 431.305 ;
    END
  END r0_addr_in[2]
  PIN r0_addr_in[3]
    DIRECTION INPUT ;
    USE SIGNAL ;
    SHAPE ABUTMENT ;
    PORT
      LAYER M3 ;
      RECT 0 434.315 0.07 434.385 ;
    END
  END r0_addr_in[3]
  PIN r0_addr_in[4]
    DIRECTION INPUT ;
    USE SIGNAL ;
    SHAPE ABUTMENT ;
    PORT
      LAYER M3 ;
      RECT 0 437.395 0.07 437.465 ;
    END
  END r0_addr_in[4]
  PIN r0_addr_in[5]
    DIRECTION INPUT ;
    USE SIGNAL ;
    SHAPE ABUTMENT ;
    PORT
      LAYER M3 ;
      RECT 0 440.475 0.07 440.545 ;
    END
  END r0_addr_in[5]
  PIN r0_addr_in[6]
    DIRECTION INPUT ;
    USE SIGNAL ;
    SHAPE ABUTMENT ;
    PORT
      LAYER M3 ;
      RECT 0 443.555 0.07 443.625 ;
    END
  END r0_addr_in[6]
  PIN r0_addr_in[7]
    DIRECTION INPUT ;
    USE SIGNAL ;
    SHAPE ABUTMENT ;
    PORT
      LAYER M3 ;
      RECT 0 446.635 0.07 446.705 ;
    END
  END r0_addr_in[7]
  PIN r0_addr_in[8]
    DIRECTION INPUT ;
    USE SIGNAL ;
    SHAPE ABUTMENT ;
    PORT
      LAYER M3 ;
      RECT 0 449.715 0.07 449.785 ;
    END
  END r0_addr_in[8]
  PIN r0_addr_in[9]
    DIRECTION INPUT ;
    USE SIGNAL ;
    SHAPE ABUTMENT ;
    PORT
      LAYER M3 ;
      RECT 0 452.795 0.07 452.865 ;
    END
  END r0_addr_in[9]
  PIN w0_we_in
    DIRECTION INPUT ;
    USE SIGNAL ;
    SHAPE ABUTMENT ;
    PORT
      LAYER M3 ;
      RECT 0 455.875 0.07 455.945 ;
    END
  END w0_we_in
  PIN w0_ce_in
    DIRECTION INPUT ;
    USE SIGNAL ;
    SHAPE ABUTMENT ;
    PORT
      LAYER M3 ;
      RECT 0 458.955 0.07 459.025 ;
    END
  END w0_ce_in
  PIN w0_clk
    DIRECTION INPUT ;
    USE SIGNAL ;
    SHAPE ABUTMENT ;
    PORT
      LAYER M3 ;
      RECT 0 462.035 0.07 462.105 ;
    END
  END w0_clk
  PIN r0_ce_in
    DIRECTION INPUT ;
    USE SIGNAL ;
    SHAPE ABUTMENT ;
    PORT
      LAYER M3 ;
      RECT 0 465.115 0.07 465.185 ;
    END
  END r0_ce_in
  PIN r0_clk
    DIRECTION INPUT ;
    USE SIGNAL ;
    SHAPE ABUTMENT ;
    PORT
      LAYER M3 ;
      RECT 0 468.195 0.07 468.265 ;
    END
  END r0_clk
  PIN VSS
    DIRECTION INOUT ;
    USE GROUND ;
    PORT
      LAYER M4 ;
      RECT 1 0.84 1.28 476.56 ;
      RECT 3.24 0.84 3.52 476.56 ;
      RECT 5.48 0.84 5.76 476.56 ;
      RECT 7.72 0.84 8 476.56 ;
      RECT 9.96 0.84 10.24 476.56 ;
      RECT 12.2 0.84 12.48 476.56 ;
      RECT 14.44 0.84 14.72 476.56 ;
      RECT 16.68 0.84 16.96 476.56 ;
      RECT 18.92 0.84 19.2 476.56 ;
      RECT 21.16 0.84 21.44 476.56 ;
      RECT 23.4 0.84 23.68 476.56 ;
      RECT 25.64 0.84 25.92 476.56 ;
      RECT 27.88 0.84 28.16 476.56 ;
      RECT 30.12 0.84 30.4 476.56 ;
      RECT 32.36 0.84 32.64 476.56 ;
      RECT 34.6 0.84 34.88 476.56 ;
      RECT 36.84 0.84 37.12 476.56 ;
      RECT 39.08 0.84 39.36 476.56 ;
      RECT 41.32 0.84 41.6 476.56 ;
      RECT 43.56 0.84 43.84 476.56 ;
      RECT 45.8 0.84 46.08 476.56 ;
      RECT 48.04 0.84 48.32 476.56 ;
      RECT 50.28 0.84 50.56 476.56 ;
      RECT 52.52 0.84 52.8 476.56 ;
      RECT 54.76 0.84 55.04 476.56 ;
      RECT 57 0.84 57.28 476.56 ;
      RECT 59.24 0.84 59.52 476.56 ;
      RECT 61.48 0.84 61.76 476.56 ;
      RECT 63.72 0.84 64 476.56 ;
      RECT 65.96 0.84 66.24 476.56 ;
      RECT 68.2 0.84 68.48 476.56 ;
      RECT 70.44 0.84 70.72 476.56 ;
      RECT 72.68 0.84 72.96 476.56 ;
      RECT 74.92 0.84 75.2 476.56 ;
      RECT 77.16 0.84 77.44 476.56 ;
      RECT 79.4 0.84 79.68 476.56 ;
      RECT 81.64 0.84 81.92 476.56 ;
      RECT 83.88 0.84 84.16 476.56 ;
      RECT 86.12 0.84 86.4 476.56 ;
      RECT 88.36 0.84 88.64 476.56 ;
      RECT 90.6 0.84 90.88 476.56 ;
      RECT 92.84 0.84 93.12 476.56 ;
      RECT 95.08 0.84 95.36 476.56 ;
      RECT 97.32 0.84 97.6 476.56 ;
      RECT 99.56 0.84 99.84 476.56 ;
      RECT 101.8 0.84 102.08 476.56 ;
      RECT 104.04 0.84 104.32 476.56 ;
      RECT 106.28 0.84 106.56 476.56 ;
      RECT 108.52 0.84 108.8 476.56 ;
      RECT 110.76 0.84 111.04 476.56 ;
      RECT 113 0.84 113.28 476.56 ;
      RECT 115.24 0.84 115.52 476.56 ;
      RECT 117.48 0.84 117.76 476.56 ;
      RECT 119.72 0.84 120 476.56 ;
      RECT 121.96 0.84 122.24 476.56 ;
      RECT 124.2 0.84 124.48 476.56 ;
      RECT 126.44 0.84 126.72 476.56 ;
      RECT 128.68 0.84 128.96 476.56 ;
      RECT 130.92 0.84 131.2 476.56 ;
      RECT 133.16 0.84 133.44 476.56 ;
      RECT 135.4 0.84 135.68 476.56 ;
      RECT 137.64 0.84 137.92 476.56 ;
      RECT 139.88 0.84 140.16 476.56 ;
      RECT 142.12 0.84 142.4 476.56 ;
      RECT 144.36 0.84 144.64 476.56 ;
      RECT 146.6 0.84 146.88 476.56 ;
      RECT 148.84 0.84 149.12 476.56 ;
      RECT 151.08 0.84 151.36 476.56 ;
      RECT 153.32 0.84 153.6 476.56 ;
      RECT 155.56 0.84 155.84 476.56 ;
      RECT 157.8 0.84 158.08 476.56 ;
      RECT 160.04 0.84 160.32 476.56 ;
      RECT 162.28 0.84 162.56 476.56 ;
      RECT 164.52 0.84 164.8 476.56 ;
      RECT 166.76 0.84 167.04 476.56 ;
      RECT 169 0.84 169.28 476.56 ;
      RECT 171.24 0.84 171.52 476.56 ;
      RECT 173.48 0.84 173.76 476.56 ;
      RECT 175.72 0.84 176 476.56 ;
      RECT 177.96 0.84 178.24 476.56 ;
      RECT 180.2 0.84 180.48 476.56 ;
      RECT 182.44 0.84 182.72 476.56 ;
      RECT 184.68 0.84 184.96 476.56 ;
      RECT 186.92 0.84 187.2 476.56 ;
      RECT 189.16 0.84 189.44 476.56 ;
      RECT 191.4 0.84 191.68 476.56 ;
      RECT 193.64 0.84 193.92 476.56 ;
      RECT 195.88 0.84 196.16 476.56 ;
      RECT 198.12 0.84 198.4 476.56 ;
      RECT 200.36 0.84 200.64 476.56 ;
      RECT 202.6 0.84 202.88 476.56 ;
      RECT 204.84 0.84 205.12 476.56 ;
      RECT 207.08 0.84 207.36 476.56 ;
      RECT 209.32 0.84 209.6 476.56 ;
      RECT 211.56 0.84 211.84 476.56 ;
      RECT 213.8 0.84 214.08 476.56 ;
      RECT 216.04 0.84 216.32 476.56 ;
      RECT 218.28 0.84 218.56 476.56 ;
      RECT 220.52 0.84 220.8 476.56 ;
      RECT 222.76 0.84 223.04 476.56 ;
      RECT 225 0.84 225.28 476.56 ;
      RECT 227.24 0.84 227.52 476.56 ;
      RECT 229.48 0.84 229.76 476.56 ;
      RECT 231.72 0.84 232 476.56 ;
      RECT 233.96 0.84 234.24 476.56 ;
      RECT 236.2 0.84 236.48 476.56 ;
      RECT 238.44 0.84 238.72 476.56 ;
      RECT 240.68 0.84 240.96 476.56 ;
      RECT 242.92 0.84 243.2 476.56 ;
      RECT 245.16 0.84 245.44 476.56 ;
      RECT 247.4 0.84 247.68 476.56 ;
      RECT 249.64 0.84 249.92 476.56 ;
      RECT 251.88 0.84 252.16 476.56 ;
      RECT 254.12 0.84 254.4 476.56 ;
      RECT 256.36 0.84 256.64 476.56 ;
      RECT 258.6 0.84 258.88 476.56 ;
      RECT 260.84 0.84 261.12 476.56 ;
      RECT 263.08 0.84 263.36 476.56 ;
      RECT 265.32 0.84 265.6 476.56 ;
      RECT 267.56 0.84 267.84 476.56 ;
    END
  END VSS
  PIN VDD
    DIRECTION INOUT ;
    USE POWER ;
    PORT
      LAYER M4 ;
      RECT 2.12 0.84 2.4 476.56 ;
      RECT 4.36 0.84 4.64 476.56 ;
      RECT 6.6 0.84 6.88 476.56 ;
      RECT 8.84 0.84 9.12 476.56 ;
      RECT 11.08 0.84 11.36 476.56 ;
      RECT 13.32 0.84 13.6 476.56 ;
      RECT 15.56 0.84 15.84 476.56 ;
      RECT 17.8 0.84 18.08 476.56 ;
      RECT 20.04 0.84 20.32 476.56 ;
      RECT 22.28 0.84 22.56 476.56 ;
      RECT 24.52 0.84 24.8 476.56 ;
      RECT 26.76 0.84 27.04 476.56 ;
      RECT 29 0.84 29.28 476.56 ;
      RECT 31.24 0.84 31.52 476.56 ;
      RECT 33.48 0.84 33.76 476.56 ;
      RECT 35.72 0.84 36 476.56 ;
      RECT 37.96 0.84 38.24 476.56 ;
      RECT 40.2 0.84 40.48 476.56 ;
      RECT 42.44 0.84 42.72 476.56 ;
      RECT 44.68 0.84 44.96 476.56 ;
      RECT 46.92 0.84 47.2 476.56 ;
      RECT 49.16 0.84 49.44 476.56 ;
      RECT 51.4 0.84 51.68 476.56 ;
      RECT 53.64 0.84 53.92 476.56 ;
      RECT 55.88 0.84 56.16 476.56 ;
      RECT 58.12 0.84 58.4 476.56 ;
      RECT 60.36 0.84 60.64 476.56 ;
      RECT 62.6 0.84 62.88 476.56 ;
      RECT 64.84 0.84 65.12 476.56 ;
      RECT 67.08 0.84 67.36 476.56 ;
      RECT 69.32 0.84 69.6 476.56 ;
      RECT 71.56 0.84 71.84 476.56 ;
      RECT 73.8 0.84 74.08 476.56 ;
      RECT 76.04 0.84 76.32 476.56 ;
      RECT 78.28 0.84 78.56 476.56 ;
      RECT 80.52 0.84 80.8 476.56 ;
      RECT 82.76 0.84 83.04 476.56 ;
      RECT 85 0.84 85.28 476.56 ;
      RECT 87.24 0.84 87.52 476.56 ;
      RECT 89.48 0.84 89.76 476.56 ;
      RECT 91.72 0.84 92 476.56 ;
      RECT 93.96 0.84 94.24 476.56 ;
      RECT 96.2 0.84 96.48 476.56 ;
      RECT 98.44 0.84 98.72 476.56 ;
      RECT 100.68 0.84 100.96 476.56 ;
      RECT 102.92 0.84 103.2 476.56 ;
      RECT 105.16 0.84 105.44 476.56 ;
      RECT 107.4 0.84 107.68 476.56 ;
      RECT 109.64 0.84 109.92 476.56 ;
      RECT 111.88 0.84 112.16 476.56 ;
      RECT 114.12 0.84 114.4 476.56 ;
      RECT 116.36 0.84 116.64 476.56 ;
      RECT 118.6 0.84 118.88 476.56 ;
      RECT 120.84 0.84 121.12 476.56 ;
      RECT 123.08 0.84 123.36 476.56 ;
      RECT 125.32 0.84 125.6 476.56 ;
      RECT 127.56 0.84 127.84 476.56 ;
      RECT 129.8 0.84 130.08 476.56 ;
      RECT 132.04 0.84 132.32 476.56 ;
      RECT 134.28 0.84 134.56 476.56 ;
      RECT 136.52 0.84 136.8 476.56 ;
      RECT 138.76 0.84 139.04 476.56 ;
      RECT 141 0.84 141.28 476.56 ;
      RECT 143.24 0.84 143.52 476.56 ;
      RECT 145.48 0.84 145.76 476.56 ;
      RECT 147.72 0.84 148 476.56 ;
      RECT 149.96 0.84 150.24 476.56 ;
      RECT 152.2 0.84 152.48 476.56 ;
      RECT 154.44 0.84 154.72 476.56 ;
      RECT 156.68 0.84 156.96 476.56 ;
      RECT 158.92 0.84 159.2 476.56 ;
      RECT 161.16 0.84 161.44 476.56 ;
      RECT 163.4 0.84 163.68 476.56 ;
      RECT 165.64 0.84 165.92 476.56 ;
      RECT 167.88 0.84 168.16 476.56 ;
      RECT 170.12 0.84 170.4 476.56 ;
      RECT 172.36 0.84 172.64 476.56 ;
      RECT 174.6 0.84 174.88 476.56 ;
      RECT 176.84 0.84 177.12 476.56 ;
      RECT 179.08 0.84 179.36 476.56 ;
      RECT 181.32 0.84 181.6 476.56 ;
      RECT 183.56 0.84 183.84 476.56 ;
      RECT 185.8 0.84 186.08 476.56 ;
      RECT 188.04 0.84 188.32 476.56 ;
      RECT 190.28 0.84 190.56 476.56 ;
      RECT 192.52 0.84 192.8 476.56 ;
      RECT 194.76 0.84 195.04 476.56 ;
      RECT 197 0.84 197.28 476.56 ;
      RECT 199.24 0.84 199.52 476.56 ;
      RECT 201.48 0.84 201.76 476.56 ;
      RECT 203.72 0.84 204 476.56 ;
      RECT 205.96 0.84 206.24 476.56 ;
      RECT 208.2 0.84 208.48 476.56 ;
      RECT 210.44 0.84 210.72 476.56 ;
      RECT 212.68 0.84 212.96 476.56 ;
      RECT 214.92 0.84 215.2 476.56 ;
      RECT 217.16 0.84 217.44 476.56 ;
      RECT 219.4 0.84 219.68 476.56 ;
      RECT 221.64 0.84 221.92 476.56 ;
      RECT 223.88 0.84 224.16 476.56 ;
      RECT 226.12 0.84 226.4 476.56 ;
      RECT 228.36 0.84 228.64 476.56 ;
      RECT 230.6 0.84 230.88 476.56 ;
      RECT 232.84 0.84 233.12 476.56 ;
      RECT 235.08 0.84 235.36 476.56 ;
      RECT 237.32 0.84 237.6 476.56 ;
      RECT 239.56 0.84 239.84 476.56 ;
      RECT 241.8 0.84 242.08 476.56 ;
      RECT 244.04 0.84 244.32 476.56 ;
      RECT 246.28 0.84 246.56 476.56 ;
      RECT 248.52 0.84 248.8 476.56 ;
      RECT 250.76 0.84 251.04 476.56 ;
      RECT 253 0.84 253.28 476.56 ;
      RECT 255.24 0.84 255.52 476.56 ;
      RECT 257.48 0.84 257.76 476.56 ;
      RECT 259.72 0.84 260 476.56 ;
      RECT 261.96 0.84 262.24 476.56 ;
      RECT 264.2 0.84 264.48 476.56 ;
      RECT 266.44 0.84 266.72 476.56 ;
    END
  END VDD
  OBS
    LAYER M1 ;
    RECT 0 0 268.09 477.4 ;
    LAYER M2 ;
    RECT 0 0 268.09 477.4 ;
  END
END ht45_leon3vtabus_tensorFile_0_0_ext_bottom

END LIBRARY
